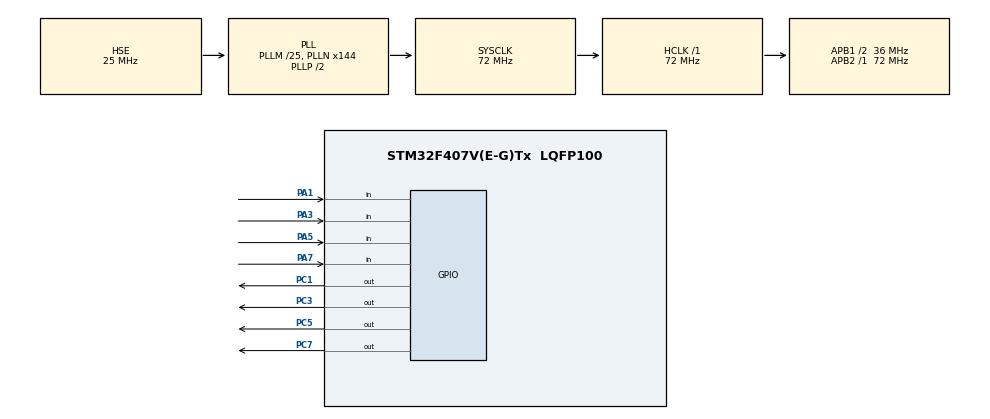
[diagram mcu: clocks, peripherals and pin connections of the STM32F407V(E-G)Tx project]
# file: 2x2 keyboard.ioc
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Mcu.Family=STM32F4
Mcu.Name=STM32F407V(E-G)Tx
Mcu.Package=LQFP100
NVIC.PriorityGroup=NVIC_PRIORITYGROUP_4
PA1.Signal=GPIO_Input
PA13.Mode=Serial_Wire
PA13.Signal=SYS_JTMS-SWDIO
PA14.Mode=Serial_Wire
PA14.Signal=SYS_JTCK-SWCLK
PA3.Signal=GPIO_Input
PA5.Signal=GPIO_Input
PA7.Signal=GPIO_Input
PC1.Signal=GPIO_Output
PC3.Signal=GPIO_Output
PC5.Signal=GPIO_Output
PC7.Signal=GPIO_Output
PH0-OSC_IN.Mode=HSE-External-Oscillator
PH0-OSC_IN.Signal=RCC_OSC_IN
PH1-OSC_OUT.Mode=HSE-External-Oscillator
PH1-OSC_OUT.Signal=RCC_OSC_OUT
ProjectManager.HeapSize=0x200
ProjectManager.StackSize=0x400
ProjectManager.TargetToolchain=STM32CubeIDE
RCC.48MHZClocksFreq_Value=36000000
RCC.AHBFreq_Value=72000000
RCC.APB1CLKDivider=RCC_HCLK_DIV2
RCC.APB1Freq_Value=36000000
RCC.APB1TimFreq_Value=72000000
RCC.APB2Freq_Value=72000000
RCC.APB2TimFreq_Value=72000000
RCC.CortexFreq_Value=72000000
RCC.HCLKFreq_Value=72000000
RCC.HSE_VALUE=25000000
RCC.HSI_VALUE=16000000
RCC.LSE_VALUE=32768
RCC.PLLM=25
RCC.PLLN=144
RCC.PLLSourceVirtual=RCC_PLLSOURCE_HSE
RCC.SYSCLKFreq_VALUE=72000000
RCC.SYSCLKSource=RCC_SYSCLKSOURCE_PLLCLK
RCC.VCOOutputFreq_Value=144000000
board=custom

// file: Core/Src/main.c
/* USER CODE BEGIN Header */
/**
  ******************************************************************************
  * @file           : main.c
  * @brief          : Main program body
  ******************************************************************************
  * @attention
  *
  * Copyright (c) 2024 STMicroelectronics.
  * All rights reserved.
  *
  * This software is licensed under terms that can be found in the LICENSE file
  * in the root directory of this software component.
  * If no LICENSE file comes with this software, it is provided AS-IS.
  *
  ******************************************************************************
  */
/* USER CODE END Header */
#include "main.h"
#include "stm32f4xx_it.h"

#define R1_Pin GPIO_PIN_1
#define R1_GPIO_Port GPIOA
#define R2_Pin GPIO_PIN_3
#define R2_GPIO_Port GPIOA
#define C1_Pin GPIO_PIN_5
#define C1_GPIO_Port GPIOA
#define C2_Pin GPIO_PIN_7
#define C2_GPIO_Port GPIOA
#define L1_Pin GPIO_PIN_1
#define L1_GPIO_Port GPIOC
#define L2_Pin GPIO_PIN_3
#define L2_GPIO_Port GPIOC
#define L3_Pin GPIO_PIN_5
#define L3_GPIO_Port GPIOC
#define L4_Pin GPIO_PIN_7
#define L4_GPIO_Port GPIOC

void SystemClock_Config(void);
static void MX_GPIO_Init(void);

int main(void)
{

  /* USER CODE BEGIN 1 */
//int row=0, col=0;
  /* USER CODE END 1 */

  /* MCU Configuration--------------------------------------------------------*/

  /* Reset of all peripherals, Initializes the Flash interface and the Systick. */
  HAL_Init();

  /* Configure the system clock */
  SystemClock_Config();

  /* Initialize all configured peripherals */
  MX_GPIO_Init();

  /* Infinite loop */
  while (1)
  {
	  scanButtons();

  }
}

void scanButtons()
{
    // Scan Row 1 (Row pin low, others high)
    HAL_GPIO_WritePin(R1_GPIO_Port, R1_Pin, GPIO_PIN_RESET);
    HAL_GPIO_WritePin(R2_GPIO_Port, R2_Pin, GPIO_PIN_SET);

    // Check Column pins
    if (HAL_GPIO_ReadPin(C1_GPIO_Port, C1_Pin) == GPIO_PIN_RESET)
    {
        // Button 1 (Row 1, Column 1) pressed
        // Handle action (e.g., toggle LED)
        HAL_GPIO_TogglePin(L1_GPIO_Port, L1_Pin);
        HAL_Delay(500); // debounce delay
    }
    if (HAL_GPIO_ReadPin(C2_GPIO_Port, C2_Pin) == GPIO_PIN_RESET)
    {
        // Button 2 (Row 1, Column 2) pressed
        // Handle action (e.g., toggle buzzer)
        HAL_GPIO_TogglePin(L2_GPIO_Port, L2_Pin);
        HAL_Delay(500); // debounce delay
    }

    // Scan Row 2 (Row pin low, others high)
    HAL_GPIO_WritePin(R1_GPIO_Port, R1_Pin, GPIO_PIN_SET);
    HAL_GPIO_WritePin(R2_GPIO_Port, R2_Pin, GPIO_PIN_RESET);

    // Check Column pins
    if (HAL_GPIO_ReadPin(C1_GPIO_Port, C1_Pin) == GPIO_PIN_RESET)
    {
        // Button 3 (Row 2, Column 1) pressed
        // Handle action
        HAL_GPIO_TogglePin(L3_GPIO_Port, L3_Pin);
        HAL_Delay(500); // debounce delay
    }
    if (HAL_GPIO_ReadPin(C2_GPIO_Port, C2_Pin) == GPIO_PIN_RESET)
    {
        // Button 4 (Row 2, Column 2) pressed
        // Handle action
        HAL_GPIO_TogglePin(L4_GPIO_Port, L4_Pin);
        HAL_Delay(500); // debounce delay
    }

    // Reset GPIO pins to original state for next scan cycle
    HAL_GPIO_WritePin(R1_GPIO_Port, R1_Pin, GPIO_PIN_SET);
    HAL_GPIO_WritePin(R2_GPIO_Port, R2_Pin, GPIO_PIN_SET);
}

void SystemClock_Config(void)
{
  RCC_OscInitTypeDef RCC_OscInitStruct = {0};
  RCC_ClkInitTypeDef RCC_ClkInitStruct = {0};

  /** Configure the main internal regulator output voltage
  */
  __HAL_RCC_PWR_CLK_ENABLE();
  __HAL_PWR_VOLTAGESCALING_CONFIG(PWR_REGULATOR_VOLTAGE_SCALE1);

  /** Initializes the RCC Oscillators according to the specified parameters
  * in the RCC_OscInitTypeDef structure.
  */
  RCC_OscInitStruct.OscillatorType = RCC_OSCILLATORTYPE_HSE;
  RCC_OscInitStruct.HSEState = RCC_HSE_ON;
  RCC_OscInitStruct.PLL.PLLState = RCC_PLL_ON;
  RCC_OscInitStruct.PLL.PLLSource = RCC_PLLSOURCE_HSE;
  RCC_OscInitStruct.PLL.PLLM = 25;
  RCC_OscInitStruct.PLL.PLLN = 144;
  RCC_OscInitStruct.PLL.PLLP = RCC_PLLP_DIV2;
  RCC_OscInitStruct.PLL.PLLQ = 4;
  if (HAL_RCC_OscConfig(&RCC_OscInitStruct) != HAL_OK)
  {
    Error_Handler();
  }

  /** Initializes the CPU, AHB and APB buses clocks
  */
  RCC_ClkInitStruct.ClockType = RCC_CLOCKTYPE_HCLK|RCC_CLOCKTYPE_SYSCLK
                              |RCC_CLOCKTYPE_PCLK1|RCC_CLOCKTYPE_PCLK2;
  RCC_ClkInitStruct.SYSCLKSource = RCC_SYSCLKSOURCE_PLLCLK;
  RCC_ClkInitStruct.AHBCLKDivider = RCC_SYSCLK_DIV1;
  RCC_ClkInitStruct.APB1CLKDivider = RCC_HCLK_DIV2;
  RCC_ClkInitStruct.APB2CLKDivider = RCC_HCLK_DIV1;

  if (HAL_RCC_ClockConfig(&RCC_ClkInitStruct, FLASH_LATENCY_2) != HAL_OK)
  {
    Error_Handler();
  }
}

static void MX_GPIO_Init(void)
{
  GPIO_InitTypeDef GPIO_InitStruct = {0};

  /* GPIO Ports Clock Enable */
  __HAL_RCC_GPIOH_CLK_ENABLE();
  __HAL_RCC_GPIOC_CLK_ENABLE();
  __HAL_RCC_GPIOA_CLK_ENABLE();

  /*Configure GPIO pin Output Level */
  //HAL_GPIO_WritePin(GPIOC, GPIO_PIN_1|GPIO_PIN_3|GPIO_PIN_5|GPIO_PIN_7, GPIO_PIN_RESET);

  // Configure GPIO pins for rows (PA0, PA1) with pull-up
      GPIO_InitStruct.Pin = R1_Pin | R2_Pin;
      GPIO_InitStruct.Mode = GPIO_MODE_OUTPUT_PP;
      GPIO_InitStruct.Pull = GPIO_PULLUP;
      GPIO_InitStruct.Speed = GPIO_SPEED_FREQ_LOW;
      HAL_GPIO_Init(GPIOA, &GPIO_InitStruct);

    // Configure GPIO pins for columns (PA2, PA3) with pull-up
        GPIO_InitStruct.Pin = C1_Pin | C2_Pin;
        GPIO_InitStruct.Mode = GPIO_MODE_INPUT;
        GPIO_InitStruct.Pull = GPIO_PULLUP;
        HAL_GPIO_Init(GPIOA, &GPIO_InitStruct);

        // Configure GPIO pins for LEDs (PB12, PB13, PB14, PB15)
          GPIO_InitStruct.Pin = L1_Pin | L2_Pin | L3_Pin | L4_Pin;
          GPIO_InitStruct.Mode = GPIO_MODE_OUTPUT_PP;
          GPIO_InitStruct.Pull = GPIO_NOPULL;
          GPIO_InitStruct.Speed = GPIO_SPEED_FREQ_LOW;
          HAL_GPIO_Init(GPIOC, &GPIO_InitStruct);

          // Ensure LEDs are initially turned off
          HAL_GPIO_WritePin(GPIOC, L1_Pin | L2_Pin | L3_Pin | L4_Pin, GPIO_PIN_RESET);

}

void Error_Handler(void)
{
  __disable_irq();
  while (1)
  {
  }
}
